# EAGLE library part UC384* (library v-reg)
SMPS Controller Source: http://www.fairchildsemi.com/ds/UC/UC3843.pdf

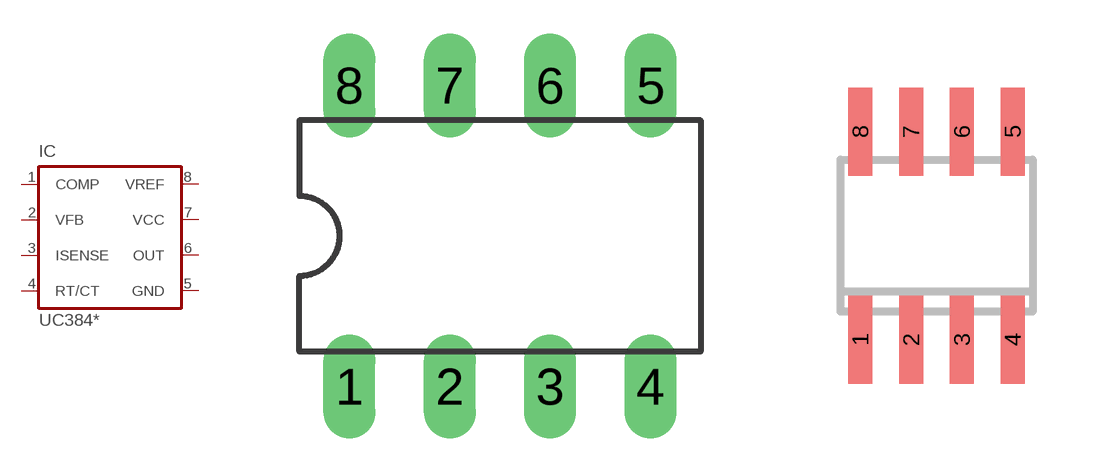
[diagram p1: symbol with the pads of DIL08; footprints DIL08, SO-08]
Designator prefix IC

## UC3842N, UC3843N, UC3844N, UC3845N  [DIL08]
1  COMP  pas
2  VFB  in
3  ISENSE  in
4  RT/CT  pas
5  GND  pwr
6  OUT  out
7  VCC  pwr
8  VREF  pas

## UC3842D1, UC3843D1, UC3844D1, UC3845D1  [SO-08]
Pads as for DIL08

## Footprint DIL08 (pad centres in mm)
Dual In Line Package
drill 0.813 long: 1 -3.81,-3.81; 2 -1.27,-3.81; 3 1.27,-3.81; 4 3.81,-3.81; 5 3.81,3.81; 6 1.27,3.81; 7 -1.27,3.81; 8 -3.81,3.81

## Footprint SO-08 (pad centres in mm)
Small Outline Narrow Plastic Gull Wing 150-mil body, package type SN
smd 0.6 x 2.2: 1 -1.905,-2.6; 2 -0.635,-2.6; 3 0.635,-2.6; 4 1.905,-2.6; 5 1.905,2.6; 6 0.635,2.6; 7 -0.635,2.6; 8 -1.905,2.6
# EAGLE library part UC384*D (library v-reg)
SMPS Controller Source: http://www.fairchildsemi.com/ds/UC/UC3843.pdf

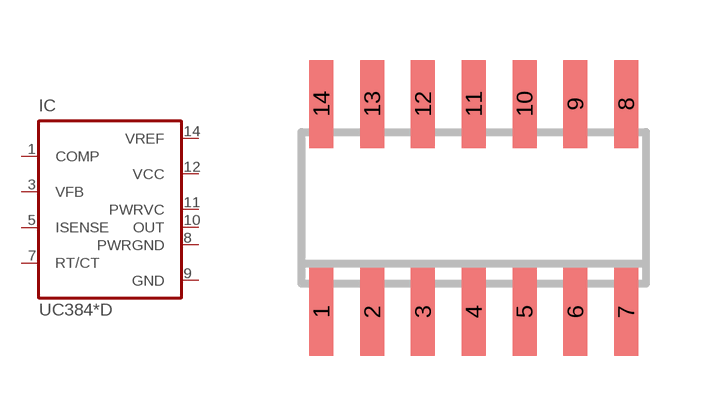
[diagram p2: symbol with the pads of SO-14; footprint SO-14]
Designator prefix IC

## UC3842D, UC3843D, UC3844D, UC3845D  [SO-14]
1  COMP  pas
3  VFB  in
5  ISENSE  in
7  RT/CT  pas
8  PWRGND  in
9  GND  pwr
10  OUT  out
11  PWRVC  in
12  VCC  pwr
14  VREF  pas

## Footprint SO-14 (pad centres in mm)
Small Outline Narrow Plastic Gull Wing 150-mil body, package type SL
smd 0.6 x 2.2: 1 -3.81,-2.6; 2 -2.54,-2.6; 3 -1.27,-2.6; 4 0,-2.6; 5 1.27,-2.6; 6 2.54,-2.6; 7 3.81,-2.6; 8 3.81,2.6; 9 2.54,2.6; 10 1.27,2.6; 11 0,2.6; 12 -1.27,2.6; 13 -2.54,2.6; 14 -3.81,2.6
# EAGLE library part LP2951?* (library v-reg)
Series of Adjustable Micropower Voltage Regulators Source: http://cache.national.com/ds/LP/LP2950.pdf

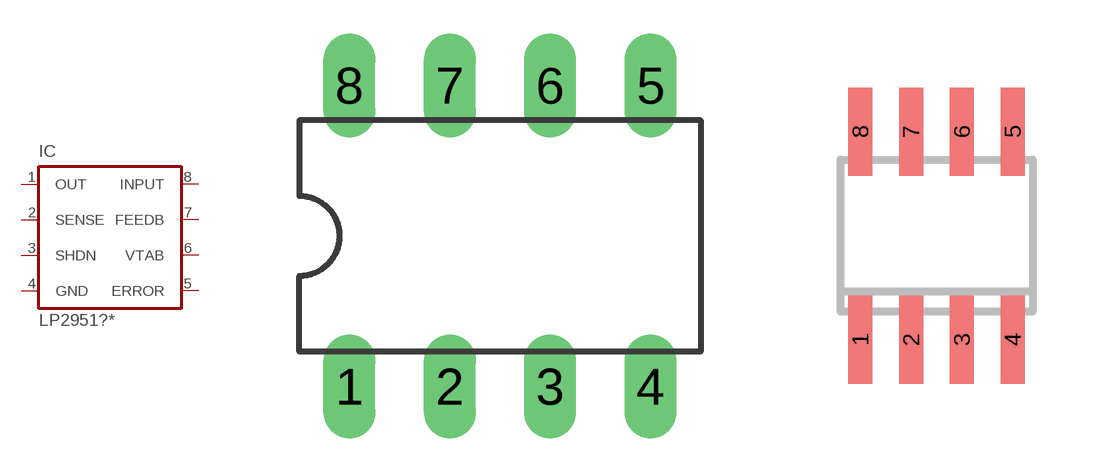
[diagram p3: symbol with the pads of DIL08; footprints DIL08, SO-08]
Designator prefix IC

## LP2951CN, LP2951CN-3.0, LP2951CN-3.3  [DIL08]
1  OUT  out
2  SENSE  in
3  SHDN  in
4  GND  pwr
5  ERROR  out
6  VTAB  in
7  FEEDB  out
8  INPUT  pas

## LP2951CM, LP2951CM-3.0, LP2951CM-3.3, LP2951CMX, LP2951CMX-3.0, LP2951CMX-3.3  [SO-08]
Pads as for DIL08

## LP2951CSD, LP2951CSD-3.0, LP2951CSD-3.3, LP2951CSDX, LP2951CSDX-3.3, LP2951CSDX3.0  [LLP8]
Pads as for DIL08

## LP2951H  [H08C]
Pads as for DIL08

## LP2951WG  [SO10C]
1  OUT  out
2  SENSE  in
3  SHDN  in
4  GND  pwr
7  ERROR  out
8  VTAB  in
9  FEEDB  out
10  INPUT  pas

## LP2951ACM, LP2951ACM-3.0, LP2951ACM-3.3, LP2951ACMX, LP2951ACMX-3.0, LP2951ACMX-3.3  [SO-08]
Pads as for DIL08

## LP2951ACSD, LP2951ACSD-3.0, LP2951ACSD-3.3, LP2951ACSDX, LP2951ACSDX-3.0, LP2951ACSDX-3.3  [LLP8]
Pads as for DIL08

## LP2951ACMM, LP2951ACMM-3.0, LP2951ACMM-3.3, LP2951ACMMX-3.0, LP2951ACMMX-3.3  [MUA08A]
Pads as for DIL08

## LP2951CMM, LP2951CMM-3.0, LP2951CMM-3.3, LP2951CMMX, LP2951CMMX-3.0, LP2951CMMX-3.3  [MUA08A]
Pads as for DIL08

## Footprint DIL08 (pad centres in mm)
Dual In Line Package
drill 0.813 long: 1 -3.81,-3.81; 2 -1.27,-3.81; 3 1.27,-3.81; 4 3.81,-3.81; 5 3.81,3.81; 6 1.27,3.81; 7 -1.27,3.81; 8 -3.81,3.81

## Footprint SO-08 (pad centres in mm)
Small Outline Narrow Plastic Gull Wing 150-mil body, package type SN
smd 0.6 x 2.2: 1 -1.905,-2.6; 2 -0.635,-2.6; 3 0.635,-2.6; 4 1.905,-2.6; 5 1.905,2.6; 6 0.635,2.6; 7 -0.635,2.6; 8 -1.905,2.6

## Footprint LLP8 (pad centres in mm)
LLP Package NS Package Number SDC08A Source: http://cache.national.com/ds/LP/LP2950.pdf
smd 0.3 x 0.6: 1 -1.2,-1.9; 2 -0.4,-1.9; 3 0.4,-1.9; 4 1.2,-1.9; 5 1.2,1.9; 6 0.4,1.9; 7 -0.4,1.9; 8 -1.2,1.9
smd 3 x 2.6: EXP 0,0

## Footprint H08C (pad centres in mm)
TO-99 National Semiconductor H08C Motorola MOT 601-04
drill 0.813 octagon: 1 -1.778,-1.778; 2 0,-2.54; 3 1.778,-1.778; 4 2.54,0; 5 1.778,1.778; 6 0,2.54; 7 -1.778,1.778; 8 -2.54,0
